VERSION 5.7 ;
  NOWIREEXTENSIONATPIN ON ;
  DIVIDERCHAR "/" ;
  BUSBITCHARS "[]" ;
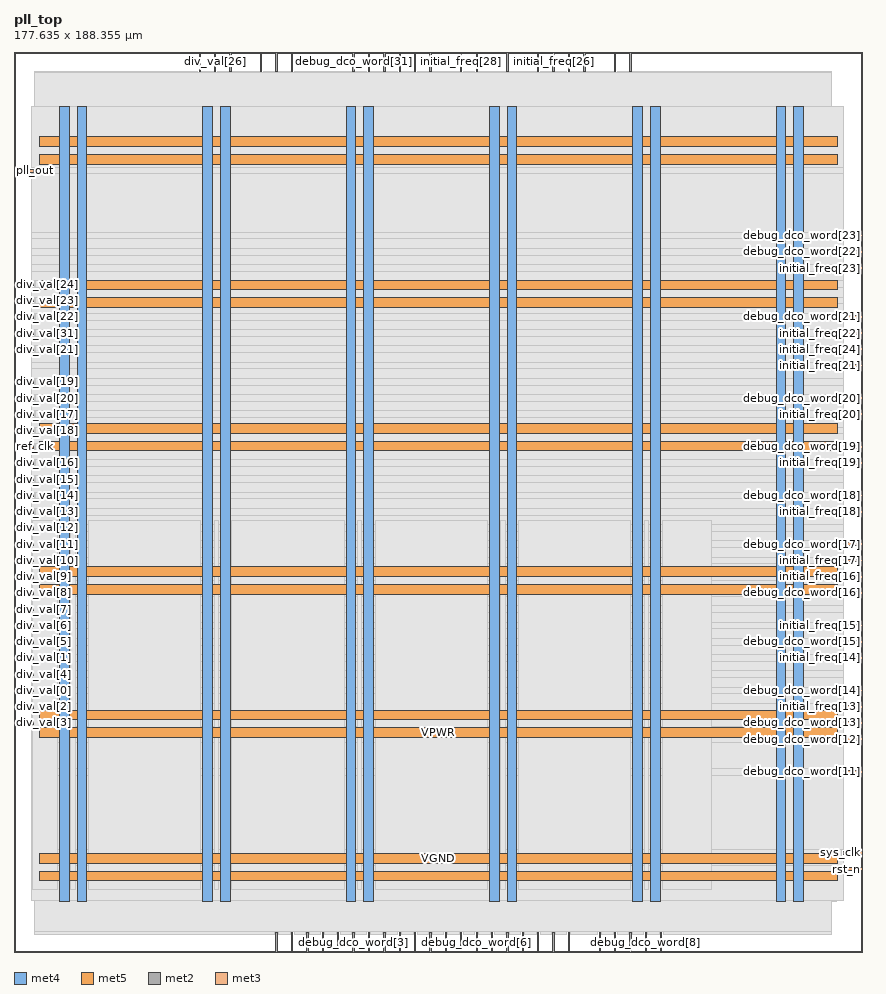
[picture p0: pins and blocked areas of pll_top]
MACRO pll_top
  CLASS BLOCK ;
  FOREIGN pll_top ;
  ORIGIN 0.000 0.000 ;
  SIZE 177.635 BY 188.355 ;
  PIN VGND
    DIRECTION INOUT ;
    USE GROUND ;
    PORT
      LAYER met4 ;
        RECT 13.220 10.640 15.220 177.040 ;
    END
    PORT
      LAYER met4 ;
        RECT 43.220 10.640 45.220 177.040 ;
    END
    PORT
      LAYER met4 ;
        RECT 73.220 10.640 75.220 177.040 ;
    END
    PORT
      LAYER met4 ;
        RECT 103.220 10.640 105.220 177.040 ;
    END
    PORT
      LAYER met4 ;
        RECT 133.220 10.640 135.220 177.040 ;
    END
    PORT
      LAYER met4 ;
        RECT 163.220 10.640 165.220 177.040 ;
    END
    PORT
      LAYER met5 ;
        RECT 5.280 18.580 172.280 20.580 ;
    END
    PORT
      LAYER met5 ;
        RECT 5.280 48.580 172.280 50.580 ;
    END
    PORT
      LAYER met5 ;
        RECT 5.280 78.580 172.280 80.580 ;
    END
    PORT
      LAYER met5 ;
        RECT 5.280 108.580 172.280 110.580 ;
    END
    PORT
      LAYER met5 ;
        RECT 5.280 138.580 172.280 140.580 ;
    END
    PORT
      LAYER met5 ;
        RECT 5.280 168.580 172.280 170.580 ;
    END
  END VGND
  PIN VPWR
    DIRECTION INOUT ;
    USE POWER ;
    PORT
      LAYER met4 ;
        RECT 9.520 10.640 11.520 177.040 ;
    END
    PORT
      LAYER met4 ;
        RECT 39.520 10.640 41.520 177.040 ;
    END
    PORT
      LAYER met4 ;
        RECT 69.520 10.640 71.520 177.040 ;
    END
    PORT
      LAYER met4 ;
        RECT 99.520 10.640 101.520 177.040 ;
    END
    PORT
      LAYER met4 ;
        RECT 129.520 10.640 131.520 177.040 ;
    END
    PORT
      LAYER met4 ;
        RECT 159.520 10.640 161.520 177.040 ;
    END
    PORT
      LAYER met5 ;
        RECT 5.280 14.880 172.280 16.880 ;
    END
    PORT
      LAYER met5 ;
        RECT 5.280 44.880 172.280 46.880 ;
    END
    PORT
      LAYER met5 ;
        RECT 5.280 74.880 172.280 76.880 ;
    END
    PORT
      LAYER met5 ;
        RECT 5.280 104.880 172.280 106.880 ;
    END
    PORT
      LAYER met5 ;
        RECT 5.280 134.880 172.280 136.880 ;
    END
    PORT
      LAYER met5 ;
        RECT 5.280 164.880 172.280 166.880 ;
    END
  END VPWR
  PIN debug_dco_word[0]
    DIRECTION OUTPUT ;
    USE SIGNAL ;
    ANTENNADIFFAREA 0.445500 ;
    PORT
      LAYER met2 ;
        RECT 54.830 0.000 55.110 4.000 ;
    END
  END debug_dco_word[0]
  PIN debug_dco_word[10]
    DIRECTION OUTPUT ;
    USE SIGNAL ;
    ANTENNADIFFAREA 0.445500 ;
    PORT
      LAYER met2 ;
        RECT 128.890 0.000 129.170 4.000 ;
    END
  END debug_dco_word[10]
  PIN debug_dco_word[11]
    DIRECTION OUTPUT ;
    USE SIGNAL ;
    ANTENNADIFFAREA 0.445500 ;
    PORT
      LAYER met3 ;
        RECT 173.635 37.440 177.635 38.040 ;
    END
  END debug_dco_word[11]
  PIN debug_dco_word[12]
    DIRECTION OUTPUT ;
    USE SIGNAL ;
    ANTENNADIFFAREA 0.445500 ;
    PORT
      LAYER met3 ;
        RECT 173.635 44.240 177.635 44.840 ;
    END
  END debug_dco_word[12]
  PIN debug_dco_word[13]
    DIRECTION OUTPUT ;
    USE SIGNAL ;
    ANTENNADIFFAREA 0.445500 ;
    PORT
      LAYER met3 ;
        RECT 173.635 47.640 177.635 48.240 ;
    END
  END debug_dco_word[13]
  PIN debug_dco_word[14]
    DIRECTION OUTPUT ;
    USE SIGNAL ;
    ANTENNADIFFAREA 0.445500 ;
    PORT
      LAYER met3 ;
        RECT 173.635 54.440 177.635 55.040 ;
    END
  END debug_dco_word[14]
  PIN debug_dco_word[15]
    DIRECTION OUTPUT ;
    USE SIGNAL ;
    ANTENNADIFFAREA 0.445500 ;
    PORT
      LAYER met3 ;
        RECT 173.635 64.640 177.635 65.240 ;
    END
  END debug_dco_word[15]
  PIN debug_dco_word[16]
    DIRECTION OUTPUT ;
    USE SIGNAL ;
    ANTENNADIFFAREA 0.445500 ;
    PORT
      LAYER met3 ;
        RECT 173.635 74.840 177.635 75.440 ;
    END
  END debug_dco_word[16]
  PIN debug_dco_word[17]
    DIRECTION OUTPUT ;
    USE SIGNAL ;
    ANTENNADIFFAREA 0.445500 ;
    PORT
      LAYER met3 ;
        RECT 173.635 85.040 177.635 85.640 ;
    END
  END debug_dco_word[17]
  PIN debug_dco_word[18]
    DIRECTION OUTPUT ;
    USE SIGNAL ;
    ANTENNADIFFAREA 0.445500 ;
    PORT
      LAYER met3 ;
        RECT 173.635 95.240 177.635 95.840 ;
    END
  END debug_dco_word[18]
  PIN debug_dco_word[19]
    DIRECTION OUTPUT ;
    USE SIGNAL ;
    ANTENNADIFFAREA 0.445500 ;
    PORT
      LAYER met3 ;
        RECT 173.635 105.440 177.635 106.040 ;
    END
  END debug_dco_word[19]
  PIN debug_dco_word[1]
    DIRECTION OUTPUT ;
    USE SIGNAL ;
    ANTENNADIFFAREA 0.445500 ;
    PORT
      LAYER met2 ;
        RECT 64.490 0.000 64.770 4.000 ;
    END
  END debug_dco_word[1]
  PIN debug_dco_word[20]
    DIRECTION OUTPUT ;
    USE SIGNAL ;
    ANTENNADIFFAREA 0.445500 ;
    PORT
      LAYER met3 ;
        RECT 173.635 115.640 177.635 116.240 ;
    END
  END debug_dco_word[20]
  PIN debug_dco_word[21]
    DIRECTION OUTPUT ;
    USE SIGNAL ;
    ANTENNADIFFAREA 0.445500 ;
    PORT
      LAYER met3 ;
        RECT 173.635 132.640 177.635 133.240 ;
    END
  END debug_dco_word[21]
  PIN debug_dco_word[22]
    DIRECTION OUTPUT ;
    USE SIGNAL ;
    ANTENNADIFFAREA 0.445500 ;
    PORT
      LAYER met3 ;
        RECT 173.635 146.240 177.635 146.840 ;
    END
  END debug_dco_word[22]
  PIN debug_dco_word[23]
    DIRECTION OUTPUT ;
    USE SIGNAL ;
    ANTENNADIFFAREA 0.445500 ;
    PORT
      LAYER met3 ;
        RECT 173.635 149.640 177.635 150.240 ;
    END
  END debug_dco_word[23]
  PIN debug_dco_word[24]
    DIRECTION OUTPUT ;
    USE SIGNAL ;
    ANTENNADIFFAREA 0.445500 ;
    PORT
      LAYER met2 ;
        RECT 128.890 184.355 129.170 188.355 ;
    END
  END debug_dco_word[24]
  PIN debug_dco_word[25]
    DIRECTION OUTPUT ;
    USE SIGNAL ;
    ANTENNADIFFAREA 0.445500 ;
    PORT
      LAYER met2 ;
        RECT 125.670 184.355 125.950 188.355 ;
    END
  END debug_dco_word[25]
  PIN debug_dco_word[26]
    DIRECTION OUTPUT ;
    USE SIGNAL ;
    ANTENNADIFFAREA 0.445500 ;
    PORT
      LAYER met2 ;
        RECT 116.010 184.355 116.290 188.355 ;
    END
  END debug_dco_word[26]
  PIN debug_dco_word[27]
    DIRECTION OUTPUT ;
    USE SIGNAL ;
    ANTENNADIFFAREA 0.445500 ;
    PORT
      LAYER met2 ;
        RECT 109.570 184.355 109.850 188.355 ;
    END
  END debug_dco_word[27]
  PIN debug_dco_word[28]
    DIRECTION OUTPUT ;
    USE SIGNAL ;
    ANTENNADIFFAREA 0.445500 ;
    PORT
      LAYER met2 ;
        RECT 96.690 184.355 96.970 188.355 ;
    END
  END debug_dco_word[28]
  PIN debug_dco_word[29]
    DIRECTION OUTPUT ;
    USE SIGNAL ;
    ANTENNADIFFAREA 0.445500 ;
    PORT
      LAYER met2 ;
        RECT 87.030 184.355 87.310 188.355 ;
    END
  END debug_dco_word[29]
  PIN debug_dco_word[2]
    DIRECTION OUTPUT ;
    USE SIGNAL ;
    ANTENNADIFFAREA 0.445500 ;
    PORT
      LAYER met2 ;
        RECT 74.150 0.000 74.430 4.000 ;
    END
  END debug_dco_word[2]
  PIN debug_dco_word[30]
    DIRECTION OUTPUT ;
    USE SIGNAL ;
    ANTENNADIFFAREA 0.445500 ;
    PORT
      LAYER met2 ;
        RECT 77.370 184.355 77.650 188.355 ;
    END
  END debug_dco_word[30]
  PIN debug_dco_word[31]
    DIRECTION OUTPUT ;
    USE SIGNAL ;
    ANTENNADIFFAREA 0.445500 ;
    PORT
      LAYER met2 ;
        RECT 70.930 184.355 71.210 188.355 ;
    END
  END debug_dco_word[31]
  PIN debug_dco_word[3]
    DIRECTION OUTPUT ;
    USE SIGNAL ;
    ANTENNADIFFAREA 0.445500 ;
    PORT
      LAYER met2 ;
        RECT 70.930 0.000 71.210 4.000 ;
    END
  END debug_dco_word[3]
  PIN debug_dco_word[4]
    DIRECTION OUTPUT ;
    USE SIGNAL ;
    ANTENNADIFFAREA 0.445500 ;
    PORT
      LAYER met2 ;
        RECT 61.270 0.000 61.550 4.000 ;
    END
  END debug_dco_word[4]
  PIN debug_dco_word[5]
    DIRECTION OUTPUT ;
    USE SIGNAL ;
    ANTENNADIFFAREA 0.445500 ;
    PORT
      LAYER met2 ;
        RECT 67.710 0.000 67.990 4.000 ;
    END
  END debug_dco_word[5]
  PIN debug_dco_word[6]
    DIRECTION OUTPUT ;
    USE SIGNAL ;
    ANTENNADIFFAREA 0.445500 ;
    PORT
      LAYER met2 ;
        RECT 96.690 0.000 96.970 4.000 ;
    END
  END debug_dco_word[6]
  PIN debug_dco_word[7]
    DIRECTION OUTPUT ;
    USE SIGNAL ;
    ANTENNADIFFAREA 0.445500 ;
    PORT
      LAYER met2 ;
        RECT 116.010 0.000 116.290 4.000 ;
    END
  END debug_dco_word[7]
  PIN debug_dco_word[8]
    DIRECTION OUTPUT ;
    USE SIGNAL ;
    ANTENNADIFFAREA 0.445500 ;
    PORT
      LAYER met2 ;
        RECT 132.110 0.000 132.390 4.000 ;
    END
  END debug_dco_word[8]
  PIN debug_dco_word[9]
    DIRECTION OUTPUT ;
    USE SIGNAL ;
    ANTENNADIFFAREA 0.445500 ;
    PORT
      LAYER met2 ;
        RECT 135.330 0.000 135.610 4.000 ;
    END
  END debug_dco_word[9]
  PIN div_val[0]
    DIRECTION INPUT ;
    USE SIGNAL ;
    ANTENNAGATEAREA 0.196500 ;
    PORT
      LAYER met3 ;
        RECT 0.000 54.440 4.000 55.040 ;
    END
  END div_val[0]
  PIN div_val[10]
    DIRECTION INPUT ;
    USE SIGNAL ;
    ANTENNAGATEAREA 0.196500 ;
    PORT
      LAYER met3 ;
        RECT 0.000 81.640 4.000 82.240 ;
    END
  END div_val[10]
  PIN div_val[11]
    DIRECTION INPUT ;
    USE SIGNAL ;
    ANTENNAGATEAREA 0.196500 ;
    PORT
      LAYER met3 ;
        RECT 0.000 85.040 4.000 85.640 ;
    END
  END div_val[11]
  PIN div_val[12]
    DIRECTION INPUT ;
    USE SIGNAL ;
    ANTENNAGATEAREA 0.196500 ;
    PORT
      LAYER met3 ;
        RECT 0.000 88.440 4.000 89.040 ;
    END
  END div_val[12]
  PIN div_val[13]
    DIRECTION INPUT ;
    USE SIGNAL ;
    ANTENNAGATEAREA 0.196500 ;
    PORT
      LAYER met3 ;
        RECT 0.000 91.840 4.000 92.440 ;
    END
  END div_val[13]
  PIN div_val[14]
    DIRECTION INPUT ;
    USE SIGNAL ;
    ANTENNAGATEAREA 0.196500 ;
    PORT
      LAYER met3 ;
        RECT 0.000 95.240 4.000 95.840 ;
    END
  END div_val[14]
  PIN div_val[15]
    DIRECTION INPUT ;
    USE SIGNAL ;
    ANTENNAGATEAREA 0.196500 ;
    PORT
      LAYER met3 ;
        RECT 0.000 98.640 4.000 99.240 ;
    END
  END div_val[15]
  PIN div_val[16]
    DIRECTION INPUT ;
    USE SIGNAL ;
    ANTENNAGATEAREA 0.196500 ;
    PORT
      LAYER met3 ;
        RECT 0.000 102.040 4.000 102.640 ;
    END
  END div_val[16]
  PIN div_val[17]
    DIRECTION INPUT ;
    USE SIGNAL ;
    ANTENNAGATEAREA 0.196500 ;
    PORT
      LAYER met3 ;
        RECT 0.000 112.240 4.000 112.840 ;
    END
  END div_val[17]
  PIN div_val[18]
    DIRECTION INPUT ;
    USE SIGNAL ;
    ANTENNAGATEAREA 0.196500 ;
    PORT
      LAYER met3 ;
        RECT 0.000 108.840 4.000 109.440 ;
    END
  END div_val[18]
  PIN div_val[19]
    DIRECTION INPUT ;
    USE SIGNAL ;
    ANTENNAGATEAREA 0.196500 ;
    PORT
      LAYER met3 ;
        RECT 0.000 119.040 4.000 119.640 ;
    END
  END div_val[19]
  PIN div_val[1]
    DIRECTION INPUT ;
    USE SIGNAL ;
    ANTENNAGATEAREA 0.196500 ;
    PORT
      LAYER met3 ;
        RECT 0.000 61.240 4.000 61.840 ;
    END
  END div_val[1]
  PIN div_val[20]
    DIRECTION INPUT ;
    USE SIGNAL ;
    ANTENNAGATEAREA 0.196500 ;
    PORT
      LAYER met3 ;
        RECT 0.000 115.640 4.000 116.240 ;
    END
  END div_val[20]
  PIN div_val[21]
    DIRECTION INPUT ;
    USE SIGNAL ;
    ANTENNAGATEAREA 0.196500 ;
    PORT
      LAYER met3 ;
        RECT 0.000 125.840 4.000 126.440 ;
    END
  END div_val[21]
  PIN div_val[22]
    DIRECTION INPUT ;
    USE SIGNAL ;
    ANTENNAGATEAREA 0.196500 ;
    PORT
      LAYER met3 ;
        RECT 0.000 132.640 4.000 133.240 ;
    END
  END div_val[22]
  PIN div_val[23]
    DIRECTION INPUT ;
    USE SIGNAL ;
    ANTENNAGATEAREA 0.196500 ;
    PORT
      LAYER met3 ;
        RECT 0.000 136.040 4.000 136.640 ;
    END
  END div_val[23]
  PIN div_val[24]
    DIRECTION INPUT ;
    USE SIGNAL ;
    ANTENNAGATEAREA 0.196500 ;
    PORT
      LAYER met3 ;
        RECT 0.000 139.440 4.000 140.040 ;
    END
  END div_val[24]
  PIN div_val[25]
    DIRECTION INPUT ;
    USE SIGNAL ;
    ANTENNAGATEAREA 0.196500 ;
    PORT
      LAYER met2 ;
        RECT 38.730 184.355 39.010 188.355 ;
    END
  END div_val[25]
  PIN div_val[26]
    DIRECTION INPUT ;
    USE SIGNAL ;
    ANTENNAGATEAREA 0.196500 ;
    PORT
      LAYER met2 ;
        RECT 41.950 184.355 42.230 188.355 ;
    END
  END div_val[26]
  PIN div_val[27]
    DIRECTION INPUT ;
    USE SIGNAL ;
    ANTENNAGATEAREA 0.196500 ;
    PORT
      LAYER met2 ;
        RECT 45.170 184.355 45.450 188.355 ;
    END
  END div_val[27]
  PIN div_val[28]
    DIRECTION INPUT ;
    USE SIGNAL ;
    ANTENNAGATEAREA 0.196500 ;
    PORT
      LAYER met2 ;
        RECT 51.610 184.355 51.890 188.355 ;
    END
  END div_val[28]
  PIN div_val[29]
    DIRECTION INPUT ;
    USE SIGNAL ;
    ANTENNAGATEAREA 0.196500 ;
    PORT
      LAYER met2 ;
        RECT 54.830 184.355 55.110 188.355 ;
    END
  END div_val[29]
  PIN div_val[2]
    DIRECTION INPUT ;
    USE SIGNAL ;
    ANTENNAGATEAREA 0.196500 ;
    PORT
      LAYER met3 ;
        RECT 0.000 51.040 4.000 51.640 ;
    END
  END div_val[2]
  PIN div_val[30]
    DIRECTION INPUT ;
    USE SIGNAL ;
    ANTENNAGATEAREA 0.196500 ;
    PORT
      LAYER met2 ;
        RECT 58.050 184.355 58.330 188.355 ;
    END
  END div_val[30]
  PIN div_val[31]
    DIRECTION INPUT ;
    USE SIGNAL ;
    ANTENNAGATEAREA 0.196500 ;
    PORT
      LAYER met3 ;
        RECT 0.000 129.240 4.000 129.840 ;
    END
  END div_val[31]
  PIN div_val[3]
    DIRECTION INPUT ;
    USE SIGNAL ;
    ANTENNAGATEAREA 0.196500 ;
    PORT
      LAYER met3 ;
        RECT 0.000 47.640 4.000 48.240 ;
    END
  END div_val[3]
  PIN div_val[4]
    DIRECTION INPUT ;
    USE SIGNAL ;
    ANTENNAGATEAREA 0.196500 ;
    PORT
      LAYER met3 ;
        RECT 0.000 57.840 4.000 58.440 ;
    END
  END div_val[4]
  PIN div_val[5]
    DIRECTION INPUT ;
    USE SIGNAL ;
    ANTENNAGATEAREA 0.196500 ;
    PORT
      LAYER met3 ;
        RECT 0.000 64.640 4.000 65.240 ;
    END
  END div_val[5]
  PIN div_val[6]
    DIRECTION INPUT ;
    USE SIGNAL ;
    ANTENNAGATEAREA 0.196500 ;
    PORT
      LAYER met3 ;
        RECT 0.000 68.040 4.000 68.640 ;
    END
  END div_val[6]
  PIN div_val[7]
    DIRECTION INPUT ;
    USE SIGNAL ;
    ANTENNAGATEAREA 0.196500 ;
    PORT
      LAYER met3 ;
        RECT 0.000 71.440 4.000 72.040 ;
    END
  END div_val[7]
  PIN div_val[8]
    DIRECTION INPUT ;
    USE SIGNAL ;
    ANTENNAGATEAREA 0.196500 ;
    PORT
      LAYER met3 ;
        RECT 0.000 74.840 4.000 75.440 ;
    END
  END div_val[8]
  PIN div_val[9]
    DIRECTION INPUT ;
    USE SIGNAL ;
    ANTENNAGATEAREA 0.196500 ;
    PORT
      LAYER met3 ;
        RECT 0.000 78.240 4.000 78.840 ;
    END
  END div_val[9]
  PIN initial_freq[0]
    DIRECTION INPUT ;
    USE SIGNAL ;
    ANTENNAGATEAREA 0.196500 ;
    PORT
      LAYER met2 ;
        RECT 58.050 0.000 58.330 4.000 ;
    END
  END initial_freq[0]
  PIN initial_freq[10]
    DIRECTION INPUT ;
    USE SIGNAL ;
    ANTENNAGATEAREA 0.196500 ;
    PORT
      LAYER met2 ;
        RECT 99.910 0.000 100.190 4.000 ;
    END
  END initial_freq[10]
  PIN initial_freq[11]
    DIRECTION INPUT ;
    USE SIGNAL ;
    ANTENNAGATEAREA 0.196500 ;
    PORT
      LAYER met2 ;
        RECT 112.790 0.000 113.070 4.000 ;
    END
  END initial_freq[11]
  PIN initial_freq[12]
    DIRECTION INPUT ;
    USE SIGNAL ;
    ANTENNAGATEAREA 0.196500 ;
    PORT
      LAYER met2 ;
        RECT 125.670 0.000 125.950 4.000 ;
    END
  END initial_freq[12]
  PIN initial_freq[13]
    DIRECTION INPUT ;
    USE SIGNAL ;
    ANTENNAGATEAREA 0.196500 ;
    PORT
      LAYER met3 ;
        RECT 173.635 51.040 177.635 51.640 ;
    END
  END initial_freq[13]
  PIN initial_freq[14]
    DIRECTION INPUT ;
    USE SIGNAL ;
    ANTENNAGATEAREA 0.196500 ;
    PORT
      LAYER met3 ;
        RECT 173.635 61.240 177.635 61.840 ;
    END
  END initial_freq[14]
  PIN initial_freq[15]
    DIRECTION INPUT ;
    USE SIGNAL ;
    ANTENNAGATEAREA 0.196500 ;
    PORT
      LAYER met3 ;
        RECT 173.635 68.040 177.635 68.640 ;
    END
  END initial_freq[15]
  PIN initial_freq[16]
    DIRECTION INPUT ;
    USE SIGNAL ;
    ANTENNAGATEAREA 0.196500 ;
    PORT
      LAYER met3 ;
        RECT 173.635 78.240 177.635 78.840 ;
    END
  END initial_freq[16]
  PIN initial_freq[17]
    DIRECTION INPUT ;
    USE SIGNAL ;
    ANTENNAGATEAREA 0.196500 ;
    PORT
      LAYER met3 ;
        RECT 173.635 81.640 177.635 82.240 ;
    END
  END initial_freq[17]
  PIN initial_freq[18]
    DIRECTION INPUT ;
    USE SIGNAL ;
    ANTENNAGATEAREA 0.196500 ;
    PORT
      LAYER met3 ;
        RECT 173.635 91.840 177.635 92.440 ;
    END
  END initial_freq[18]
  PIN initial_freq[19]
    DIRECTION INPUT ;
    USE SIGNAL ;
    ANTENNAGATEAREA 0.196500 ;
    PORT
      LAYER met3 ;
        RECT 173.635 102.040 177.635 102.640 ;
    END
  END initial_freq[19]
  PIN initial_freq[1]
    DIRECTION INPUT ;
    USE SIGNAL ;
    ANTENNAGATEAREA 0.196500 ;
    PORT
      LAYER met2 ;
        RECT 93.470 0.000 93.750 4.000 ;
    END
  END initial_freq[1]
  PIN initial_freq[20]
    DIRECTION INPUT ;
    USE SIGNAL ;
    ANTENNAGATEAREA 0.196500 ;
    PORT
      LAYER met3 ;
        RECT 173.635 112.240 177.635 112.840 ;
    END
  END initial_freq[20]
  PIN initial_freq[21]
    DIRECTION INPUT ;
    USE SIGNAL ;
    ANTENNAGATEAREA 0.196500 ;
    PORT
      LAYER met3 ;
        RECT 173.635 122.440 177.635 123.040 ;
    END
  END initial_freq[21]
  PIN initial_freq[22]
    DIRECTION INPUT ;
    USE SIGNAL ;
    ANTENNAGATEAREA 0.196500 ;
    PORT
      LAYER met3 ;
        RECT 173.635 129.240 177.635 129.840 ;
    END
  END initial_freq[22]
  PIN initial_freq[23]
    DIRECTION INPUT ;
    USE SIGNAL ;
    ANTENNAGATEAREA 0.196500 ;
    PORT
      LAYER met3 ;
        RECT 173.635 142.840 177.635 143.440 ;
    END
  END initial_freq[23]
  PIN initial_freq[24]
    DIRECTION INPUT ;
    USE SIGNAL ;
    ANTENNAGATEAREA 0.196500 ;
    PORT
      LAYER met3 ;
        RECT 173.635 125.840 177.635 126.440 ;
    END
  END initial_freq[24]
  PIN initial_freq[25]
    DIRECTION INPUT ;
    USE SIGNAL ;
    ANTENNAGATEAREA 0.196500 ;
    PORT
      LAYER met2 ;
        RECT 119.230 184.355 119.510 188.355 ;
    END
  END initial_freq[25]
  PIN initial_freq[26]
    DIRECTION INPUT ;
    USE SIGNAL ;
    ANTENNAGATEAREA 0.196500 ;
    PORT
      LAYER met2 ;
        RECT 112.790 184.355 113.070 188.355 ;
    END
  END initial_freq[26]
  PIN initial_freq[27]
    DIRECTION INPUT ;
    USE SIGNAL ;
    ANTENNAGATEAREA 0.196500 ;
    PORT
      LAYER met2 ;
        RECT 103.130 184.355 103.410 188.355 ;
    END
  END initial_freq[27]
  PIN initial_freq[28]
    DIRECTION INPUT ;
    USE SIGNAL ;
    ANTENNAGATEAREA 0.196500 ;
    PORT
      LAYER met2 ;
        RECT 93.470 184.355 93.750 188.355 ;
    END
  END initial_freq[28]
  PIN initial_freq[29]
    DIRECTION INPUT ;
    USE SIGNAL ;
    ANTENNAGATEAREA 0.196500 ;
    PORT
      LAYER met2 ;
        RECT 83.810 184.355 84.090 188.355 ;
    END
  END initial_freq[29]
  PIN initial_freq[2]
    DIRECTION INPUT ;
    USE SIGNAL ;
    ANTENNAGATEAREA 0.196500 ;
    PORT
      LAYER met2 ;
        RECT 87.030 0.000 87.310 4.000 ;
    END
  END initial_freq[2]
  PIN initial_freq[30]
    DIRECTION INPUT ;
    USE SIGNAL ;
    ANTENNAGATEAREA 0.196500 ;
    PORT
      LAYER met2 ;
        RECT 80.590 184.355 80.870 188.355 ;
    END
  END initial_freq[30]
  PIN initial_freq[31]
    DIRECTION INPUT ;
    USE SIGNAL ;
    ANTENNAGATEAREA 0.196500 ;
    PORT
      LAYER met2 ;
        RECT 74.150 184.355 74.430 188.355 ;
    END
  END initial_freq[31]
  PIN initial_freq[3]
    DIRECTION INPUT ;
    USE SIGNAL ;
    ANTENNAGATEAREA 0.196500 ;
    PORT
      LAYER met2 ;
        RECT 80.590 0.000 80.870 4.000 ;
    END
  END initial_freq[3]
  PIN initial_freq[4]
    DIRECTION INPUT ;
    USE SIGNAL ;
    ANTENNAGATEAREA 0.196500 ;
    PORT
      LAYER met2 ;
        RECT 83.810 0.000 84.090 4.000 ;
    END
  END initial_freq[4]
  PIN initial_freq[5]
    DIRECTION INPUT ;
    USE SIGNAL ;
    ANTENNAGATEAREA 0.196500 ;
    PORT
      LAYER met2 ;
        RECT 77.370 0.000 77.650 4.000 ;
    END
  END initial_freq[5]
  PIN initial_freq[6]
    DIRECTION INPUT ;
    USE SIGNAL ;
    ANTENNAGATEAREA 0.196500 ;
    PORT
      LAYER met2 ;
        RECT 90.250 0.000 90.530 4.000 ;
    END
  END initial_freq[6]
  PIN initial_freq[7]
    DIRECTION INPUT ;
    USE SIGNAL ;
    ANTENNAGATEAREA 0.196500 ;
    PORT
      LAYER met2 ;
        RECT 103.130 0.000 103.410 4.000 ;
    END
  END initial_freq[7]
  PIN initial_freq[8]
    DIRECTION INPUT ;
    USE SIGNAL ;
    ANTENNAGATEAREA 0.196500 ;
    PORT
      LAYER met2 ;
        RECT 122.450 0.000 122.730 4.000 ;
    END
  END initial_freq[8]
  PIN initial_freq[9]
    DIRECTION INPUT ;
    USE SIGNAL ;
    ANTENNAGATEAREA 0.196500 ;
    PORT
      LAYER met2 ;
        RECT 109.570 0.000 109.850 4.000 ;
    END
  END initial_freq[9]
  PIN lock_detect
    DIRECTION OUTPUT ;
    USE SIGNAL ;
    ANTENNADIFFAREA 0.445500 ;
    PORT
      LAYER met2 ;
        RECT 106.350 0.000 106.630 4.000 ;
    END
  END lock_detect
  PIN pll_out
    DIRECTION OUTPUT ;
    USE SIGNAL ;
    ANTENNADIFFAREA 0.445500 ;
    PORT
      LAYER met3 ;
        RECT 0.000 163.240 4.000 163.840 ;
    END
  END pll_out
  PIN ref_clk
    DIRECTION INPUT ;
    USE SIGNAL ;
    ANTENNAGATEAREA 0.196500 ;
    PORT
      LAYER met3 ;
        RECT 0.000 105.440 4.000 106.040 ;
    END
  END ref_clk
  PIN rst_n
    DIRECTION INPUT ;
    USE SIGNAL ;
    ANTENNAGATEAREA 0.196500 ;
    PORT
      LAYER met3 ;
        RECT 173.635 17.040 177.635 17.640 ;
    END
  END rst_n
  PIN sys_clk
    DIRECTION INPUT ;
    USE SIGNAL ;
    ANTENNAGATEAREA 0.852000 ;
    PORT
      LAYER met3 ;
        RECT 173.635 20.440 177.635 21.040 ;
    END
  END sys_clk
  OBS
      LAYER nwell ;
        RECT 5.330 10.795 172.230 176.990 ;
      LAYER li1 ;
        RECT 5.520 10.795 172.040 176.885 ;
      LAYER met1 ;
        RECT 4.210 10.640 172.040 177.040 ;
      LAYER met2 ;
        RECT 4.230 184.075 38.450 184.355 ;
        RECT 39.290 184.075 41.670 184.355 ;
        RECT 42.510 184.075 44.890 184.355 ;
        RECT 45.730 184.075 51.330 184.355 ;
        RECT 52.170 184.075 54.550 184.355 ;
        RECT 55.390 184.075 57.770 184.355 ;
        RECT 58.610 184.075 70.650 184.355 ;
        RECT 71.490 184.075 73.870 184.355 ;
        RECT 74.710 184.075 77.090 184.355 ;
        RECT 77.930 184.075 80.310 184.355 ;
        RECT 81.150 184.075 83.530 184.355 ;
        RECT 84.370 184.075 86.750 184.355 ;
        RECT 87.590 184.075 93.190 184.355 ;
        RECT 94.030 184.075 96.410 184.355 ;
        RECT 97.250 184.075 102.850 184.355 ;
        RECT 103.690 184.075 109.290 184.355 ;
        RECT 110.130 184.075 112.510 184.355 ;
        RECT 113.350 184.075 115.730 184.355 ;
        RECT 116.570 184.075 118.950 184.355 ;
        RECT 119.790 184.075 125.390 184.355 ;
        RECT 126.230 184.075 128.610 184.355 ;
        RECT 129.450 184.075 171.020 184.355 ;
        RECT 4.230 4.280 171.020 184.075 ;
        RECT 4.230 3.670 54.550 4.280 ;
        RECT 55.390 3.670 57.770 4.280 ;
        RECT 58.610 3.670 60.990 4.280 ;
        RECT 61.830 3.670 64.210 4.280 ;
        RECT 65.050 3.670 67.430 4.280 ;
        RECT 68.270 3.670 70.650 4.280 ;
        RECT 71.490 3.670 73.870 4.280 ;
        RECT 74.710 3.670 77.090 4.280 ;
        RECT 77.930 3.670 80.310 4.280 ;
        RECT 81.150 3.670 83.530 4.280 ;
        RECT 84.370 3.670 86.750 4.280 ;
        RECT 87.590 3.670 89.970 4.280 ;
        RECT 90.810 3.670 93.190 4.280 ;
        RECT 94.030 3.670 96.410 4.280 ;
        RECT 97.250 3.670 99.630 4.280 ;
        RECT 100.470 3.670 102.850 4.280 ;
        RECT 103.690 3.670 106.070 4.280 ;
        RECT 106.910 3.670 109.290 4.280 ;
        RECT 110.130 3.670 112.510 4.280 ;
        RECT 113.350 3.670 115.730 4.280 ;
        RECT 116.570 3.670 122.170 4.280 ;
        RECT 123.010 3.670 125.390 4.280 ;
        RECT 126.230 3.670 128.610 4.280 ;
        RECT 129.450 3.670 131.830 4.280 ;
        RECT 132.670 3.670 135.050 4.280 ;
        RECT 135.890 3.670 171.020 4.280 ;
      LAYER met3 ;
        RECT 3.750 164.240 173.635 176.965 ;
        RECT 4.400 162.840 173.635 164.240 ;
        RECT 3.750 150.640 173.635 162.840 ;
        RECT 3.750 149.240 173.235 150.640 ;
        RECT 3.750 147.240 173.635 149.240 ;
        RECT 3.750 145.840 173.235 147.240 ;
        RECT 3.750 143.840 173.635 145.840 ;
        RECT 3.750 142.440 173.235 143.840 ;
        RECT 3.750 140.440 173.635 142.440 ;
        RECT 4.400 139.040 173.635 140.440 ;
        RECT 3.750 137.040 173.635 139.040 ;
        RECT 4.400 135.640 173.635 137.040 ;
        RECT 3.750 133.640 173.635 135.640 ;
        RECT 4.400 132.240 173.235 133.640 ;
        RECT 3.750 130.240 173.635 132.240 ;
        RECT 4.400 128.840 173.235 130.240 ;
        RECT 3.750 126.840 173.635 128.840 ;
        RECT 4.400 125.440 173.235 126.840 ;
        RECT 3.750 123.440 173.635 125.440 ;
        RECT 3.750 122.040 173.235 123.440 ;
        RECT 3.750 120.040 173.635 122.040 ;
        RECT 4.400 118.640 173.635 120.040 ;
        RECT 3.750 116.640 173.635 118.640 ;
        RECT 4.400 115.240 173.235 116.640 ;
        RECT 3.750 113.240 173.635 115.240 ;
        RECT 4.400 111.840 173.235 113.240 ;
        RECT 3.750 109.840 173.635 111.840 ;
        RECT 4.400 108.440 173.635 109.840 ;
        RECT 3.750 106.440 173.635 108.440 ;
        RECT 4.400 105.040 173.235 106.440 ;
        RECT 3.750 103.040 173.635 105.040 ;
        RECT 4.400 101.640 173.235 103.040 ;
        RECT 3.750 99.640 173.635 101.640 ;
        RECT 4.400 98.240 173.635 99.640 ;
        RECT 3.750 96.240 173.635 98.240 ;
        RECT 4.400 94.840 173.235 96.240 ;
        RECT 3.750 92.840 173.635 94.840 ;
        RECT 4.400 91.440 173.235 92.840 ;
        RECT 3.750 89.440 173.635 91.440 ;
        RECT 4.400 88.040 173.635 89.440 ;
        RECT 3.750 86.040 173.635 88.040 ;
        RECT 4.400 84.640 173.235 86.040 ;
        RECT 3.750 82.640 173.635 84.640 ;
        RECT 4.400 81.240 173.235 82.640 ;
        RECT 3.750 79.240 173.635 81.240 ;
        RECT 4.400 77.840 173.235 79.240 ;
        RECT 3.750 75.840 173.635 77.840 ;
        RECT 4.400 74.440 173.235 75.840 ;
        RECT 3.750 72.440 173.635 74.440 ;
        RECT 4.400 71.040 173.635 72.440 ;
        RECT 3.750 69.040 173.635 71.040 ;
        RECT 4.400 67.640 173.235 69.040 ;
        RECT 3.750 65.640 173.635 67.640 ;
        RECT 4.400 64.240 173.235 65.640 ;
        RECT 3.750 62.240 173.635 64.240 ;
        RECT 4.400 60.840 173.235 62.240 ;
        RECT 3.750 58.840 173.635 60.840 ;
        RECT 4.400 57.440 173.635 58.840 ;
        RECT 3.750 55.440 173.635 57.440 ;
        RECT 4.400 54.040 173.235 55.440 ;
        RECT 3.750 52.040 173.635 54.040 ;
        RECT 4.400 50.640 173.235 52.040 ;
        RECT 3.750 48.640 173.635 50.640 ;
        RECT 4.400 47.240 173.235 48.640 ;
        RECT 3.750 45.240 173.635 47.240 ;
        RECT 3.750 43.840 173.235 45.240 ;
        RECT 3.750 38.440 173.635 43.840 ;
        RECT 3.750 37.040 173.235 38.440 ;
        RECT 3.750 21.440 173.635 37.040 ;
        RECT 3.750 20.040 173.235 21.440 ;
        RECT 3.750 18.040 173.635 20.040 ;
        RECT 3.750 16.640 173.235 18.040 ;
        RECT 3.750 10.715 173.635 16.640 ;
      LAYER met4 ;
        RECT 3.975 13.095 9.120 90.265 ;
        RECT 11.920 13.095 12.820 90.265 ;
        RECT 15.620 13.095 39.120 90.265 ;
        RECT 41.920 13.095 42.820 90.265 ;
        RECT 45.620 13.095 69.120 90.265 ;
        RECT 71.920 13.095 72.820 90.265 ;
        RECT 75.620 13.095 99.120 90.265 ;
        RECT 101.920 13.095 102.820 90.265 ;
        RECT 105.620 13.095 129.120 90.265 ;
        RECT 131.920 13.095 132.820 90.265 ;
        RECT 135.620 13.095 145.985 90.265 ;
  END
END pll_top
END LIBRARY

